# Copyright 2020 The SkyWater PDK Authors
#
# Licensed under the Apache License, Version 2.0 (the "License");
# you may not use this file except in compliance with the License.
# You may obtain a copy of the License at
#
#     https://www.apache.org/licenses/LICENSE-2.0
#
# Unless required by applicable law or agreed to in writing, software
# distributed under the License is distributed on an "AS IS" BASIS,
# WITHOUT WARRANTIES OR CONDITIONS OF ANY KIND, either express or implied.
# See the License for the specific language governing permissions and
# limitations under the License.
#
# SPDX-License-Identifier: Apache-2.0

VERSION 5.7 ;

BUSBITCHARS "[]" ;
DIVIDERCHAR "/" ;

UNITS
  TIME NANOSECONDS 1 ;
  CAPACITANCE PICOFARADS 1 ;
  RESISTANCE OHMS 1 ;
  DATABASE MICRONS 10000 ;
END UNITS

MANUFACTURINGGRID 0.0001 ;

PROPERTYDEFINITIONS
  LAYER LEF58_TYPE STRING ;
END PROPERTYDEFINITIONS

# High density, single height
SITE unithd
  SYMMETRY Y ;
  CLASS CORE ;
  SIZE 0.0615 BY 0.3632 ;
END unithd

# High density, double height
SITE unithddbl
  SYMMETRY Y ;
  CLASS CORE ;
  SIZE 0.0615 BY 0.7264 ;
END unithddbl

LAYER nwell
  TYPE MASTERSLICE ;
  PROPERTY LEF58_TYPE "TYPE NWELL ;" ;
END nwell

LAYER pwell
  TYPE MASTERSLICE ;
  PROPERTY LEF58_TYPE "TYPE PWELL ;" ;
END pwell

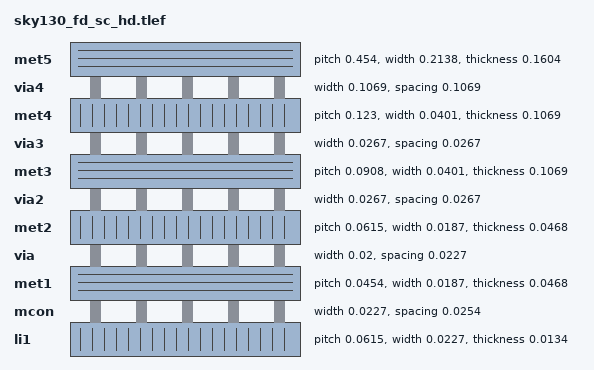
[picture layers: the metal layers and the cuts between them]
LAYER li1
  TYPE ROUTING ;
  DIRECTION VERTICAL ;

  PITCH 0.0615 0.0454 ;
  OFFSET 0.0307 0.0227 ;

  WIDTH 0.0227 ;          # LI 0.1336
  # SPACING  0.17 ;     # LI 2
  SPACINGTABLE
      PARALLELRUNLENGTH 0
     WIDTH 0 0.0227 ;
  AREA 0.001002 ;         # LI 0.107143
  THICKNESS 0.0134 ;
  EDGECAPACITANCE 40.697E-6 ;
  CAPACITANCE CPERSQDIST 36.9866E-6 ;
  RESISTANCE RPERSQ 12.2 ;

  ANTENNAMODEL OXIDE1 ;
  ANTENNADIFFSIDEAREARATIO PWL ( ( 0 75 ) ( 0.0125 75 ) ( 0.0225 85.125 ) ( 22.5 10200 ) ) ;
END li1

LAYER mcon
  TYPE CUT ;

  WIDTH 0.0227 ;                # Mcon 0.1336
  SPACING 0.0254 ;              # Mcon 0.2673
  ENCLOSURE BELOW 0 0 ;       # Mcon 0.534522
  ENCLOSURE ABOVE 0.0040 0.0080 ; # Met0.133631 0.534522 / Met0.133631 0.668153

  ANTENNADIFFAREARATIO PWL ( ( 0 3 ) ( 0.0125 3 ) ( 0.0225 3.405 ) ( 22.5 408 ) ) ;
  DCCURRENTDENSITY AVERAGE 0.36 ; # mA per via Iavg_max at Tj = 90oC

END mcon

LAYER met1
  TYPE ROUTING ;
  DIRECTION HORIZONTAL ;

  PITCH 0.0454 ;
  OFFSET 0.0227 ;

  WIDTH 0.0187 ;                     # Met0.1336 0.1336
  # SPACING 0.14 ;                 # Met1 2
  # SPACING 0.28 RANGE 3.001 100 ; # Met1 3b
  SPACINGTABLE
      PARALLELRUNLENGTH 0
     WIDTH 0 0.0187
     WIDTH 0.4009 0.0374 ;
  AREA 0.001482 ;                     # Met0.017857 0.107143
  THICKNESS 0.0468 ;

  ANTENNAMODEL OXIDE1 ;
  ANTENNADIFFSIDEAREARATIO PWL ( ( 0 400 ) ( 0.0125 400 ) ( 0.0225 2609 ) ( 22.5 11600 ) ) ;

  EDGECAPACITANCE 40.567E-6 ;
  CAPACITANCE CPERSQDIST 25.7784E-6 ;
  DCCURRENTDENSITY AVERAGE 2.8 ; # mA/um Iavg_max at Tj = 90oC
  ACCURRENTDENSITY RMS 6.1 ; # mA/um Irms_max at Tj = 90oC
  MAXIMUMDENSITY 70 ;
  DENSITYCHECKWINDOW 700 700 ;
  DENSITYCHECKSTEP 70 ;

  RESISTANCE RPERSQ 0.125 ;
END met1

LAYER via
  TYPE CUT ;
  WIDTH 0.0200 ;                  # Via 0.1336a
  SPACING 0.0227 ;                # Via 0.2673
  ENCLOSURE BELOW 0.0073 0.0113 ; # Via 0.534522a / Via 0.668153a
  ENCLOSURE ABOVE 0.0073 0.0113 ; # Met0.267261 0.534522 / Met0.267261 0.668153

  ANTENNADIFFAREARATIO PWL ( ( 0 6 ) ( 0.0125 6 ) ( 0.0225 6.81 ) ( 22.5 816 ) ) ;
  DCCURRENTDENSITY AVERAGE 0.29 ; # mA per via Iavg_max at Tj = 90oC
END via

LAYER met2
  TYPE ROUTING ;
  DIRECTION VERTICAL ;

  PITCH 0.0615 ;
  OFFSET 0.0307 ;

  WIDTH 0.0187 ;                        # Met0.2673 0.1336
  # SPACING  0.14 ;                   # Met2 2
  # SPACING  0.28 RANGE 3.001 100 ;   # Met2 3b
  SPACINGTABLE
      PARALLELRUNLENGTH 0
     WIDTH 0 0.0187
     WIDTH 0.4009 0.0374 ;
  AREA 0.001207 ;                       # Met0.035714 0.107143
  THICKNESS 0.0468 ;

  EDGECAPACITANCE 37.759E-6 ;
  CAPACITANCE CPERSQDIST 16.9423E-6 ;
  RESISTANCE RPERSQ 0.125 ;
  DCCURRENTDENSITY AVERAGE 2.8 ; # mA/um Iavg_max at Tj = 90oC
  ACCURRENTDENSITY RMS 6.1 ; # mA/um Irms_max at Tj = 90oC

  ANTENNAMODEL OXIDE1 ;
  ANTENNADIFFSIDEAREARATIO PWL ( ( 0 400 ) ( 0.0125 400 ) ( 0.0225 2609 ) ( 22.5 11600 ) ) ;

  MAXIMUMDENSITY 70 ;
  DENSITYCHECKWINDOW 700 700 ;
  DENSITYCHECKSTEP 70 ;
END met2

# ******** Layer via2, type routing, number 44 **************
LAYER via2
  TYPE CUT ;
  WIDTH 0.0267 ;                   # Via0.2673 0.1336
  SPACING 0.0267 ;                 # Via0.2673 0.2673
  ENCLOSURE BELOW 0.0053 0.0113 ;  # Via0.267261 0.534522
  ENCLOSURE ABOVE 0.0086 0.0086 ; # Met0.400892 0.534522
  ANTENNADIFFAREARATIO PWL ( ( 0 6 ) ( 0.0125 6 ) ( 0.0225 6.81 ) ( 22.5 816 ) ) ;
  DCCURRENTDENSITY AVERAGE 0.48 ; # mA per via Iavg_max at Tj = 90oC
END via2

LAYER met3
  TYPE ROUTING ;
  DIRECTION HORIZONTAL ;

  PITCH 0.0908 ;
  OFFSET 0.0454 ;

  WIDTH 0.0401 ;              # Met0.4009 0.1336
  # SPACING 0.3 ;          # Met3 2
  SPACINGTABLE
      PARALLELRUNLENGTH 0
     WIDTH 0 0.0401
     WIDTH 0.4009 0.0535 ;
  AREA 0.004286 ;              # Met0.053571 0.107143
  THICKNESS 0.1069 ;

  EDGECAPACITANCE 40.989E-6 ;
  CAPACITANCE CPERSQDIST 12.3729E-6 ;
  RESISTANCE RPERSQ 0.047 ;
  DCCURRENTDENSITY AVERAGE 6.8 ; # mA/um Iavg_max at Tj = 90oC
  ACCURRENTDENSITY RMS 14.9 ; # mA/um Irms_max at Tj = 90oC

  ANTENNAMODEL OXIDE1 ;
  ANTENNADIFFSIDEAREARATIO PWL ( ( 0 400 ) ( 0.0125 400 ) ( 0.0225 2609 ) ( 22.5 11600 ) ) ;

  MAXIMUMDENSITY 70 ;
  DENSITYCHECKWINDOW 700 700 ;
  DENSITYCHECKSTEP 70 ;
END met3

LAYER via3
  TYPE CUT ;
  WIDTH 0.0267 ;                   # Via0.4009 0.1336
  SPACING 0.0267 ;                 # Via0.4009 0.2673
  ENCLOSURE BELOW 0.0080 0.0120 ;   # Via0.400892 0.534522 / Via0.400892 0.668153
  ENCLOSURE ABOVE 0.0086 0.0086 ; # Met0.534522 0.400892
  ANTENNADIFFAREARATIO PWL ( ( 0 6 ) ( 0.0125 6 ) ( 0.0225 6.81 ) ( 22.5 816 ) ) ;
  DCCURRENTDENSITY AVERAGE 0.48 ; # mA per via Iavg_max at Tj = 90oC
END via3

LAYER met4
  TYPE ROUTING ;
  DIRECTION VERTICAL ;

  PITCH 0.1230 ;
  OFFSET 0.0615 ;

  WIDTH 0.0401 ;             # Met0.5345 0.1336
  # SPACING  0.3 ;             # Met4 2
  SPACINGTABLE
      PARALLELRUNLENGTH 0
     WIDTH 0 0.0401
     WIDTH 0.4009 0.0535 ;
  AREA 0.004286 ;            # Met0.071429 0.071429a

  THICKNESS 0.1069 ;

  EDGECAPACITANCE 36.676E-6 ;
  CAPACITANCE CPERSQDIST 8.41537E-6 ;
  RESISTANCE RPERSQ 0.047 ;
  DCCURRENTDENSITY AVERAGE 6.8 ; # mA/um Iavg_max at Tj = 90oC
  ACCURRENTDENSITY RMS 14.9 ; # mA/um Irms_max at Tj = 90oC

  ANTENNAMODEL OXIDE1 ;
  ANTENNADIFFSIDEAREARATIO PWL ( ( 0 400 ) ( 0.0125 400 ) ( 0.0225 2609 ) ( 22.5 11600 ) ) ;

  MAXIMUMDENSITY 70 ;
  DENSITYCHECKWINDOW 700 700 ;
  DENSITYCHECKSTEP 70 ;
END met4

LAYER via4
  TYPE CUT ;

  WIDTH 0.1069 ;                 # Via0.5345 0.1336
  SPACING 0.1069 ;               # Via0.5345 0.2673
  ENCLOSURE BELOW 0.0253 0.0253 ; # Via0.534522 0.534522
  ENCLOSURE ABOVE 0.0414 0.0414 ; # Met0.668153 0.400892
  ANTENNADIFFAREARATIO PWL ( ( 0 6 ) ( 0.0125 6 ) ( 0.0225 6.81 ) ( 22.5 816 ) ) ;
  DCCURRENTDENSITY AVERAGE 2.49 ; # mA per via Iavg_max at Tj = 90oC
END via4

LAYER met5
  TYPE ROUTING ;
  DIRECTION HORIZONTAL ;

  PITCH 0.4540 ;
  OFFSET 0.2272 ;

  WIDTH 0.2138 ;            # Met0.6682 0.1336
  #SPACING  1.6 ;        # Met5 2
  SPACINGTABLE
      PARALLELRUNLENGTH 0
     WIDTH 0 0.2138 ;
  AREA 0.071429 ;               # Met0.089286 0.071429

  THICKNESS 0.1604 ;

  EDGECAPACITANCE 38.851E-6 ;
  CAPACITANCE CPERSQDIST 6.32063E-6 ;
  RESISTANCE RPERSQ 0.0285 ;
  DCCURRENTDENSITY AVERAGE 10.17 ; # mA/um Iavg_max at Tj = 90oC
  ACCURRENTDENSITY RMS 22.34 ; # mA/um Irms_max at Tj = 90oC

  ANTENNAMODEL OXIDE1 ;
  ANTENNADIFFSIDEAREARATIO PWL ( ( 0 400 ) ( 0.0125 400 ) ( 0.0225 2609 ) ( 22.5 11600 ) ) ;
END met5


### Routing via cells section   ###
# Plus via rule, metals are along the prefered direction
VIA L1M1_PR DEFAULT
  LAYER mcon ;
  RECT -0.0114 -0.0114 0.0114 0.0114 ;
  LAYER li1 ;
  RECT -0.0114 -0.0114 0.0114 0.0114 ;
  LAYER met1 ;
  RECT -0.0194 -0.0154 0.0194 0.0154 ;
END L1M1_PR

VIARULE L1M1_PR GENERATE
  LAYER li1 ;
  ENCLOSURE 0 0 ;
  LAYER met1 ;
  ENCLOSURE 0.0080 0.0040 ;
  LAYER mcon ;
  RECT -0.0114 -0.0114 0.0114 0.0114 ;
  SPACING 0.0481 BY 0.0481 ;
END L1M1_PR

# Plus via rule, metals are along the non prefered direction
VIA L1M1_PR_R DEFAULT
  LAYER mcon ;
  RECT -0.0114 -0.0114 0.0114 0.0114 ;
  LAYER li1 ;
  RECT -0.0114 -0.0114 0.0114 0.0114 ;
  LAYER met1 ;
  RECT -0.0154 -0.0194 0.0154 0.0194 ;
END L1M1_PR_R

VIARULE L1M1_PR_R GENERATE
  LAYER li1 ;
  ENCLOSURE 0 0 ;
  LAYER met1 ;
  ENCLOSURE 0.0040 0.0080 ;
  LAYER mcon ;
  RECT -0.0114 -0.0114 0.0114 0.0114 ;
  SPACING 0.0481 BY 0.0481 ;
END L1M1_PR_R

# Minus via rule, lower layer metal is along prefered direction
VIA L1M1_PR_M DEFAULT
  LAYER mcon ;
  RECT -0.0114 -0.0114 0.0114 0.0114 ;
  LAYER li1 ;
  RECT -0.0114 -0.0114 0.0114 0.0114 ;
  LAYER met1 ;
  RECT -0.0154 -0.0194 0.0154 0.0194 ;
END L1M1_PR_M

VIARULE L1M1_PR_M GENERATE
  LAYER li1 ;
  ENCLOSURE 0 0 ;
  LAYER met1 ;
  ENCLOSURE 0.0040 0.0080 ;
  LAYER mcon ;
  RECT -0.0114 -0.0114 0.0114 0.0114 ;
  SPACING 0.0481 BY 0.0481 ;
END L1M1_PR_M

# Minus via rule, upper layer metal is along prefered direction
VIA L1M1_PR_MR DEFAULT
  LAYER mcon ;
  RECT -0.0114 -0.0114 0.0114 0.0114 ;
  LAYER li1 ;
  RECT -0.0114 -0.0114 0.0114 0.0114 ;
  LAYER met1 ;
  RECT -0.0194 -0.0154 0.0194 0.0154 ;
END L1M1_PR_MR

VIARULE L1M1_PR_MR GENERATE
  LAYER li1 ;
  ENCLOSURE 0 0 ;
  LAYER met1 ;
  ENCLOSURE 0.0080 0.0040 ;
  LAYER mcon ;
  RECT -0.0114 -0.0114 0.0114 0.0114 ;
  SPACING 0.0481 BY 0.0481 ;
END L1M1_PR_MR

# Centered via rule, we really do not want to use it
VIA L1M1_PR_C DEFAULT
  LAYER mcon ;
  RECT -0.0114 -0.0114 0.0114 0.0114 ;
  LAYER li1 ;
  RECT -0.0114 -0.0114 0.0114 0.0114 ;
  LAYER met1 ;
  RECT -0.0194 -0.0194 0.0194 0.0194 ;
END L1M1_PR_C

VIARULE L1M1_PR_C GENERATE
  LAYER li1 ;
  ENCLOSURE 0 0 ;
  LAYER met1 ;
  ENCLOSURE 0.0080 0.0080 ;
  LAYER mcon ;
  RECT -0.0114 -0.0114 0.0114 0.0114 ;
  SPACING 0.0481 BY 0.0481 ;
END L1M1_PR_C

# Plus via rule, metals are along the prefered direction
VIA M1M2_PR DEFAULT
  LAYER via ;
  RECT -0.0100 -0.0100 0.0100 0.0100 ;
  LAYER met1 ;
  RECT -0.0214 -0.0174 0.0214 0.0174 ;
  LAYER met2 ;
  RECT -0.0174 -0.0214 0.0174 0.0214 ;
END M1M2_PR

VIARULE M1M2_PR GENERATE
  LAYER met1 ;
  ENCLOSURE 0.0113 0.0073 ;
  LAYER met2 ;
  ENCLOSURE 0.0073 0.0113 ;
  LAYER via ;
  RECT -0.0100 -0.0100 0.0100 0.0100 ;
  SPACING 0.0428 BY 0.0428 ;
END M1M2_PR

# Plus via rule, metals are along the non prefered direction
VIA M1M2_PR_R DEFAULT
  LAYER via ;
  RECT -0.0100 -0.0100 0.0100 0.0100 ;
  LAYER met1 ;
  RECT -0.0174 -0.0214 0.0174 0.0214 ;
  LAYER met2 ;
  RECT -0.0214 -0.0174 0.0214 0.0174 ;
END M1M2_PR_R

VIARULE M1M2_PR_R GENERATE
  LAYER met1 ;
  ENCLOSURE 0.0073 0.0113 ;
  LAYER met2 ;
  ENCLOSURE 0.0113 0.0073 ;
  LAYER via ;
  RECT -0.0100 -0.0100 0.0100 0.0100 ;
  SPACING 0.0428 BY 0.0428 ;
END M1M2_PR_R

# Minus via rule, lower layer metal is along prefered direction
VIA M1M2_PR_M DEFAULT
  LAYER via ;
  RECT -0.0100 -0.0100 0.0100 0.0100 ;
  LAYER met1 ;
  RECT -0.0214 -0.0174 0.0214 0.0174 ;
  LAYER met2 ;
  RECT -0.0214 -0.0174 0.0214 0.0174 ;
END M1M2_PR_M

VIARULE M1M2_PR_M GENERATE
  LAYER met1 ;
  ENCLOSURE 0.0113 0.0073 ;
  LAYER met2 ;
  ENCLOSURE 0.0113 0.0073 ;
  LAYER via ;
  RECT -0.0100 -0.0100 0.0100 0.0100 ;
  SPACING 0.0428 BY 0.0428 ;
END M1M2_PR_M

# Minus via rule, upper layer metal is along prefered direction
VIA M1M2_PR_MR DEFAULT
  LAYER via ;
  RECT -0.0100 -0.0100 0.0100 0.0100 ;
  LAYER met1 ;
  RECT -0.0174 -0.0214 0.0174 0.0214 ;
  LAYER met2 ;
  RECT -0.0174 -0.0214 0.0174 0.0214 ;
END M1M2_PR_MR

VIARULE M1M2_PR_MR GENERATE
  LAYER met1 ;
  ENCLOSURE 0.0073 0.0113 ;
  LAYER met2 ;
  ENCLOSURE 0.0073 0.0113 ;
  LAYER via ;
  RECT -0.0100 -0.0100 0.0100 0.0100 ;
  SPACING 0.0428 BY 0.0428 ;
END M1M2_PR_MR

# Centered via rule, we really do not want to use it
VIA M1M2_PR_C DEFAULT
  LAYER via ;
  RECT -0.0100 -0.0100 0.0100 0.0100 ;
  LAYER met1 ;
  RECT -0.0214 -0.0214 0.0214 0.0214 ;
  LAYER met2 ;
  RECT -0.0214 -0.0214 0.0214 0.0214 ;
END M1M2_PR_C

VIARULE M1M2_PR_C GENERATE
  LAYER met1 ;
  ENCLOSURE 0.0113 0.0113 ;
  LAYER met2 ;
  ENCLOSURE 0.0113 0.0113 ;
  LAYER via ;
  RECT -0.0100 -0.0100 0.0100 0.0100 ;
  SPACING 0.0428 BY 0.0428 ;
END M1M2_PR_C

# Plus via rule, metals are along the prefered direction
VIA M2M3_PR DEFAULT
  LAYER via2 ;
  RECT -0.0134 -0.0134 0.0134 0.0134 ;
  LAYER met2 ;
  RECT -0.0187 -0.0247 0.0187 0.0247 ;
  LAYER met3 ;
  RECT -0.0220 -0.0220 0.0220 0.0220 ;
END M2M3_PR

VIARULE M2M3_PR GENERATE
  LAYER met2 ;
  ENCLOSURE 0.0053 0.0113 ;
  LAYER met3 ;
  ENCLOSURE 0.0086 0.0086 ;
  LAYER via2 ;
  RECT -0.0134 -0.0134 0.0134 0.0134 ;
  SPACING 0.0535 BY 0.0535 ;
END M2M3_PR

# Plus via rule, metals are along the non prefered direction
VIA M2M3_PR_R DEFAULT
  LAYER via2 ;
  RECT -0.0134 -0.0134 0.0134 0.0134 ;
  LAYER met2 ;
  RECT -0.0247 -0.0187 0.0247 0.0187 ;
  LAYER met3 ;
  RECT -0.0220 -0.0220 0.0220 0.0220 ;
END M2M3_PR_R

VIARULE M2M3_PR_R GENERATE
  LAYER met2 ;
  ENCLOSURE 0.0113 0.0053 ;
  LAYER met3 ;
  ENCLOSURE 0.0086 0.0086 ;
  LAYER via2 ;
  RECT -0.0134 -0.0134 0.0134 0.0134 ;
  SPACING 0.0535 BY 0.0535 ;
END M2M3_PR_R

# Minus via rule, lower layer metal is along prefered direction
VIA M2M3_PR_M DEFAULT
  LAYER via2 ;
  RECT -0.0134 -0.0134 0.0134 0.0134 ;
  LAYER met2 ;
  RECT -0.0187 -0.0247 0.0187 0.0247 ;
  LAYER met3 ;
  RECT -0.0220 -0.0220 0.0220 0.0220 ;
END M2M3_PR_M

VIARULE M2M3_PR_M GENERATE
  LAYER met2 ;
  ENCLOSURE 0.0053 0.0113 ;
  LAYER met3 ;
  ENCLOSURE 0.0086 0.0086 ;
  LAYER via2 ;
  RECT -0.0134 -0.0134 0.0134 0.0134 ;
  SPACING 0.0535 BY 0.0535 ;
END M2M3_PR_M

# Minus via rule, upper layer metal is along prefered direction
VIA M2M3_PR_MR DEFAULT
  LAYER via2 ;
  RECT -0.0134 -0.0134 0.0134 0.0134 ;
  LAYER met2 ;
  RECT -0.0247 -0.0187 0.0247 0.0187 ;
  LAYER met3 ;
  RECT -0.0220 -0.0220 0.0220 0.0220 ;
END M2M3_PR_MR

VIARULE M2M3_PR_MR GENERATE
  LAYER met2 ;
  ENCLOSURE 0.0113 0.0053 ;
  LAYER met3 ;
  ENCLOSURE 0.0086 0.0086 ;
  LAYER via2 ;
  RECT -0.0134 -0.0134 0.0134 0.0134 ;
  SPACING 0.0535 BY 0.0535 ;
END M2M3_PR_MR

# Centered via rule, we really do not want to use it
VIA M2M3_PR_C DEFAULT
  LAYER via2 ;
  RECT -0.0134 -0.0134 0.0134 0.0134 ;
  LAYER met2 ;
  RECT -0.0247 -0.0247 0.0247 0.0247 ;
  LAYER met3 ;
  RECT -0.0220 -0.0220 0.0220 0.0220 ;
END M2M3_PR_C

VIARULE M2M3_PR_C GENERATE
  LAYER met2 ;
  ENCLOSURE 0.0113 0.0113 ;
  LAYER met3 ;
  ENCLOSURE 0.0086 0.0086 ;
  LAYER via2 ;
  RECT -0.0134 -0.0134 0.0134 0.0134 ;
  SPACING 0.0535 BY 0.0535 ;
END M2M3_PR_C

# Plus via rule, metals are along the prefered direction
VIA M3M4_PR DEFAULT
  LAYER via3 ;
  RECT -0.0134 -0.0134 0.0134 0.0134 ;
  LAYER met3 ;
  RECT -0.0254 -0.0214 0.0254 0.0214 ;
  LAYER met4 ;
  RECT -0.0220 -0.0220 0.0220 0.0220 ;
END M3M4_PR

VIARULE M3M4_PR GENERATE
  LAYER met3 ;
  ENCLOSURE 0.0120 0.0080 ;
  LAYER met4 ;
  ENCLOSURE 0.0086 0.0086 ;
  LAYER via3 ;
  RECT -0.0134 -0.0134 0.0134 0.0134 ;
  SPACING 0.0535 BY 0.0535 ;
END M3M4_PR

# Plus via rule, metals are along the non prefered direction
VIA M3M4_PR_R DEFAULT
  LAYER via3 ;
  RECT -0.0134 -0.0134 0.0134 0.0134 ;
  LAYER met3 ;
  RECT -0.0214 -0.0254 0.0214 0.0254 ;
  LAYER met4 ;
  RECT -0.0220 -0.0220 0.0220 0.0220 ;
END M3M4_PR_R

VIARULE M3M4_PR_R GENERATE
  LAYER met3 ;
  ENCLOSURE 0.0080 0.0120 ;
  LAYER met4 ;
  ENCLOSURE 0.0086 0.0086 ;
  LAYER via3 ;
  RECT -0.0134 -0.0134 0.0134 0.0134 ;
  SPACING 0.0535 BY 0.0535 ;
END M3M4_PR_R

# Minus via rule, lower layer metal is along prefered direction
VIA M3M4_PR_M DEFAULT
  LAYER via3 ;
  RECT -0.0134 -0.0134 0.0134 0.0134 ;
  LAYER met3 ;
  RECT -0.0254 -0.0214 0.0254 0.0214 ;
  LAYER met4 ;
  RECT -0.0220 -0.0220 0.0220 0.0220 ;
END M3M4_PR_M

VIARULE M3M4_PR_M GENERATE
  LAYER met3 ;
  ENCLOSURE 0.0120 0.0080 ;
  LAYER met4 ;
  ENCLOSURE 0.0086 0.0086 ;
  LAYER via3 ;
  RECT -0.0134 -0.0134 0.0134 0.0134 ;
  SPACING 0.0535 BY 0.0535 ;
END M3M4_PR_M

# Minus via rule, upper layer metal is along prefered direction
VIA M3M4_PR_MR DEFAULT
  LAYER via3 ;
  RECT -0.0134 -0.0134 0.0134 0.0134 ;
  LAYER met3 ;
  RECT -0.0214 -0.0254 0.0214 0.0254 ;
  LAYER met4 ;
  RECT -0.0220 -0.0220 0.0220 0.0220 ;
END M3M4_PR_MR

VIARULE M3M4_PR_MR GENERATE
  LAYER met3 ;
  ENCLOSURE 0.0080 0.0120 ;
  LAYER met4 ;
  ENCLOSURE 0.0086 0.0086 ;
  LAYER via3 ;
  RECT -0.0134 -0.0134 0.0134 0.0134 ;
  SPACING 0.0535 BY 0.0535 ;
END M3M4_PR_MR

# Centered via rule, we really do not want to use it
VIA M3M4_PR_C DEFAULT
  LAYER via3 ;
  RECT -0.0134 -0.0134 0.0134 0.0134 ;
  LAYER met3 ;
  RECT -0.0254 -0.0254 0.0254 0.0254 ;
  LAYER met4 ;
  RECT -0.0220 -0.0220 0.0220 0.0220 ;
END M3M4_PR_C

VIARULE M3M4_PR_C GENERATE
  LAYER met3 ;
  ENCLOSURE 0.0120 0.0120 ;
  LAYER met4 ;
  ENCLOSURE 0.0086 0.0086 ;
  LAYER via3 ;
  RECT -0.0134 -0.0134 0.0134 0.0134 ;
  SPACING 0.0535 BY 0.0535 ;
END M3M4_PR_C

# Plus via rule, metals are along the prefered direction
VIA M4M5_PR DEFAULT
  LAYER via4 ;
  RECT -0.0535 -0.0535 0.0535 0.0535 ;
  LAYER met4 ;
  RECT -0.0788 -0.0788 0.0788 0.0788 ;
  LAYER met5 ;
  RECT -0.0949 -0.0949 0.0949 0.0949 ;
END M4M5_PR

VIARULE M4M5_PR GENERATE
  LAYER met4 ;
  ENCLOSURE 0.0253 0.0253 ;
  LAYER met5 ;
  ENCLOSURE 0.0414 0.0414 ;
  LAYER via4 ;
  RECT -0.0535 -0.0535 0.0535 0.0535 ;
  SPACING 0.2138 BY 0.2138 ;
END M4M5_PR

# Plus via rule, metals are along the non prefered direction
VIA M4M5_PR_R DEFAULT
  LAYER via4 ;
  RECT -0.0535 -0.0535 0.0535 0.0535 ;
  LAYER met4 ;
  RECT -0.0788 -0.0788 0.0788 0.0788 ;
  LAYER met5 ;
  RECT -0.0949 -0.0949 0.0949 0.0949 ;
END M4M5_PR_R

VIARULE M4M5_PR_R GENERATE
  LAYER met4 ;
  ENCLOSURE 0.0253 0.0253 ;
  LAYER met5 ;
  ENCLOSURE 0.0414 0.0414 ;
  LAYER via4 ;
  RECT -0.0535 -0.0535 0.0535 0.0535 ;
  SPACING 0.2138 BY 0.2138 ;
END M4M5_PR_R

# Minus via rule, lower layer metal is along prefered direction
VIA M4M5_PR_M DEFAULT
  LAYER via4 ;
  RECT -0.0535 -0.0535 0.0535 0.0535 ;
  LAYER met4 ;
  RECT -0.0788 -0.0788 0.0788 0.0788 ;
  LAYER met5 ;
  RECT -0.0949 -0.0949 0.0949 0.0949 ;
END M4M5_PR_M

VIARULE M4M5_PR_M GENERATE
  LAYER met4 ;
  ENCLOSURE 0.0253 0.0253 ;
  LAYER met5 ;
  ENCLOSURE 0.0414 0.0414 ;
  LAYER via4 ;
  RECT -0.0535 -0.0535 0.0535 0.0535 ;
  SPACING 0.2138 BY 0.2138 ;
END M4M5_PR_M

# Minus via rule, upper layer metal is along prefered direction
VIA M4M5_PR_MR DEFAULT
  LAYER via4 ;
  RECT -0.0535 -0.0535 0.0535 0.0535 ;
  LAYER met4 ;
  RECT -0.0788 -0.0788 0.0788 0.0788 ;
  LAYER met5 ;
  RECT -0.0949 -0.0949 0.0949 0.0949 ;
END M4M5_PR_MR

VIARULE M4M5_PR_MR GENERATE
  LAYER met4 ;
  ENCLOSURE 0.0253 0.0253 ;
  LAYER met5 ;
  ENCLOSURE 0.0414 0.0414 ;
  LAYER via4 ;
  RECT -0.0535 -0.0535 0.0535 0.0535 ;
  SPACING 0.2138 BY 0.2138 ;
END M4M5_PR_MR

# Centered via rule, we really do not want to use it
VIA M4M5_PR_C DEFAULT
  LAYER via4 ;
  RECT -0.0535 -0.0535 0.0535 0.0535 ;
  LAYER met4 ;
  RECT -0.0788 -0.0788 0.0788 0.0788 ;
  LAYER met5 ;
  RECT -0.0949 -0.0949 0.0949 0.0949 ;
END M4M5_PR_C

VIARULE M4M5_PR_C GENERATE
  LAYER met4 ;
  ENCLOSURE 0.0253 0.0253 ;
  LAYER met5 ;
  ENCLOSURE 0.0414 0.0414 ;
  LAYER via4 ;
  RECT -0.0535 -0.0535 0.0535 0.0535 ;
  SPACING 0.2138 BY 0.2138 ;
END M4M5_PR_C
###  end of single via cells   ###

END LIBRARY
